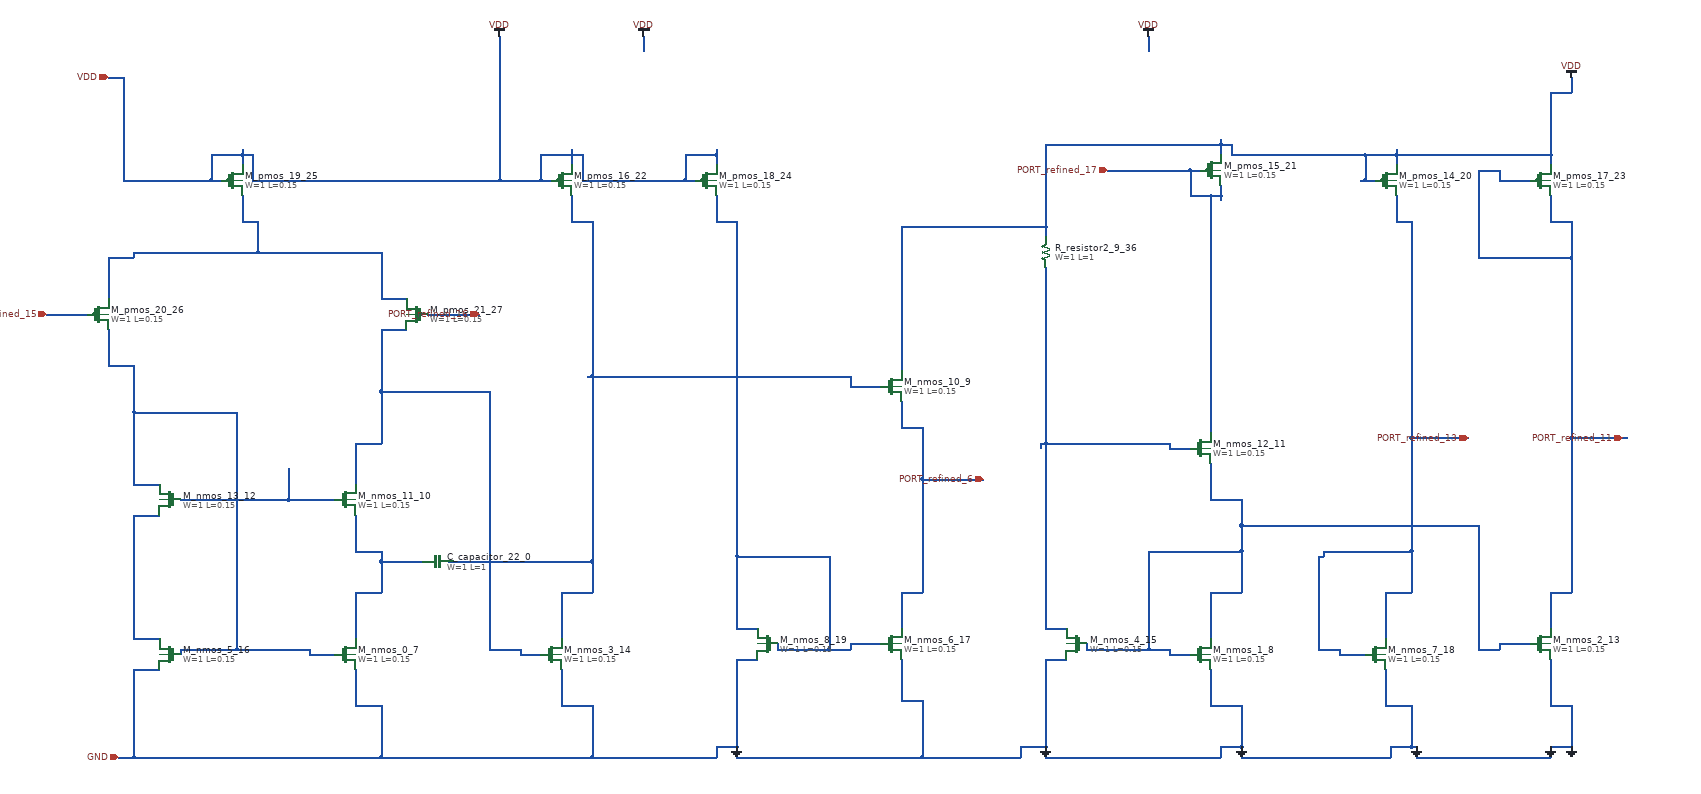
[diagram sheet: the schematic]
v {xschem version=3.4.8 file_version=1.2}
G {}
K {}
V {}
S {}
E {}
C {sky130_fd_pr/cap_mim_m3_1.sym} 920 1120 1 0 {name="C_capacitor_22_0" model=cap_mim_m3_1 W=1 L=1 MF=1 spiceprefix=X}
C {devices/gnd.sym} 3120 1480 0 0 {name="l_gnd_45_1" lab="GND"}
C {devices/gnd.sym} 1500 1480 0 0 {name="l_gnd_47_2" lab="GND"}
C {devices/gnd.sym} 2100 1480 0 0 {name="l_gnd_48_3" lab="GND"}
C {devices/gnd.sym} 3080 1480 0 0 {name="l_gnd_49_4" lab="GND"}
C {devices/gnd.sym} 2820 1480 0 0 {name="l_gnd_50_5" lab="GND"}
C {devices/gnd.sym} 2480 1480 0 0 {name="l_gnd_51_6" lab="GND"}
C {sky130_fd_pr/nfet3_01v8.sym} 740 1300 0 0 {name="M_nmos_0_7"
W=1
L=0.15
body=GND
nf=1
mult=1
ad="expr('int((@nf + 1)/2) * @W / @nf * 0.29')"
pd="expr('2*int((@nf + 1)/2) * (@W / @nf + 0.29)')"
as="expr('int((@nf + 2)/2) * @W / @nf * 0.29')"
ps="expr('2*int((@nf + 2)/2) * (@W / @nf + 0.29)')"
nrd="expr('0.29 / @W ')" nrs="expr('0.29 / @W ')"
sa=0 sb=0 sd=0
model=nfet_01v8
spiceprefix=X
}
C {sky130_fd_pr/nfet3_01v8.sym} 2400 1300 0 0 {name="M_nmos_1_8"
W=1
L=0.15
body=GND
nf=1
mult=1
ad="expr('int((@nf + 1)/2) * @W / @nf * 0.29')"
pd="expr('2*int((@nf + 1)/2) * (@W / @nf + 0.29)')"
as="expr('int((@nf + 2)/2) * @W / @nf * 0.29')"
ps="expr('2*int((@nf + 2)/2) * (@W / @nf + 0.29)')"
nrd="expr('0.29 / @W ')" nrs="expr('0.29 / @W ')"
sa=0 sb=0 sd=0
model=nfet_01v8
spiceprefix=X
}
C {sky130_fd_pr/nfet3_01v8.sym} 1800 780 0 0 {name="M_nmos_10_9"
W=1
L=0.15
body=GND
nf=1
mult=1
ad="expr('int((@nf + 1)/2) * @W / @nf * 0.29')"
pd="expr('2*int((@nf + 1)/2) * (@W / @nf + 0.29)')"
as="expr('int((@nf + 2)/2) * @W / @nf * 0.29')"
ps="expr('2*int((@nf + 2)/2) * (@W / @nf + 0.29)')"
nrd="expr('0.29 / @W ')" nrs="expr('0.29 / @W ')"
sa=0 sb=0 sd=0
model=nfet_01v8
spiceprefix=X
}
C {sky130_fd_pr/nfet3_01v8.sym} 740 1000 0 0 {name="M_nmos_11_10"
W=1
L=0.15
body=GND
nf=1
mult=1
ad="expr('int((@nf + 1)/2) * @W / @nf * 0.29')"
pd="expr('2*int((@nf + 1)/2) * (@W / @nf + 0.29)')"
as="expr('int((@nf + 2)/2) * @W / @nf * 0.29')"
ps="expr('2*int((@nf + 2)/2) * (@W / @nf + 0.29)')"
nrd="expr('0.29 / @W ')" nrs="expr('0.29 / @W ')"
sa=0 sb=0 sd=0
model=nfet_01v8
spiceprefix=X
}
C {sky130_fd_pr/nfet3_01v8.sym} 2400 900 0 0 {name="M_nmos_12_11"
W=1
L=0.15
body=GND
nf=1
mult=1
ad="expr('int((@nf + 1)/2) * @W / @nf * 0.29')"
pd="expr('2*int((@nf + 1)/2) * (@W / @nf + 0.29)')"
as="expr('int((@nf + 2)/2) * @W / @nf * 0.29')"
ps="expr('2*int((@nf + 2)/2) * (@W / @nf + 0.29)')"
nrd="expr('0.29 / @W ')" nrs="expr('0.29 / @W ')"
sa=0 sb=0 sd=0
model=nfet_01v8
spiceprefix=X
}
C {sky130_fd_pr/nfet3_01v8.sym} 400 1000 0 1 {name="M_nmos_13_12"
W=1
L=0.15
body=GND
nf=1
mult=1
ad="expr('int((@nf + 1)/2) * @W / @nf * 0.29')"
pd="expr('2*int((@nf + 1)/2) * (@W / @nf + 0.29)')"
as="expr('int((@nf + 2)/2) * @W / @nf * 0.29')"
ps="expr('2*int((@nf + 2)/2) * (@W / @nf + 0.29)')"
nrd="expr('0.29 / @W ')" nrs="expr('0.29 / @W ')"
sa=0 sb=0 sd=0
model=nfet_01v8
spiceprefix=X
}
C {sky130_fd_pr/nfet3_01v8.sym} 3060 1280 0 0 {name="M_nmos_2_13"
W=1
L=0.15
body=GND
nf=1
mult=1
ad="expr('int((@nf + 1)/2) * @W / @nf * 0.29')"
pd="expr('2*int((@nf + 1)/2) * (@W / @nf + 0.29)')"
as="expr('int((@nf + 2)/2) * @W / @nf * 0.29')"
ps="expr('2*int((@nf + 2)/2) * (@W / @nf + 0.29)')"
nrd="expr('0.29 / @W ')" nrs="expr('0.29 / @W ')"
sa=0 sb=0 sd=0
model=nfet_01v8
spiceprefix=X
}
C {sky130_fd_pr/nfet3_01v8.sym} 1140 1300 0 0 {name="M_nmos_3_14"
W=1
L=0.15
body=GND
nf=1
mult=1
ad="expr('int((@nf + 1)/2) * @W / @nf * 0.29')"
pd="expr('2*int((@nf + 1)/2) * (@W / @nf + 0.29)')"
as="expr('int((@nf + 2)/2) * @W / @nf * 0.29')"
ps="expr('2*int((@nf + 2)/2) * (@W / @nf + 0.29)')"
nrd="expr('0.29 / @W ')" nrs="expr('0.29 / @W ')"
sa=0 sb=0 sd=0
model=nfet_01v8
spiceprefix=X
}
C {sky130_fd_pr/nfet3_01v8.sym} 2160 1280 0 1 {name="M_nmos_4_15"
W=1
L=0.15
body=GND
nf=1
mult=1
ad="expr('int((@nf + 1)/2) * @W / @nf * 0.29')"
pd="expr('2*int((@nf + 1)/2) * (@W / @nf + 0.29)')"
as="expr('int((@nf + 2)/2) * @W / @nf * 0.29')"
ps="expr('2*int((@nf + 2)/2) * (@W / @nf + 0.29)')"
nrd="expr('0.29 / @W ')" nrs="expr('0.29 / @W ')"
sa=0 sb=0 sd=0
model=nfet_01v8
spiceprefix=X
}
C {sky130_fd_pr/nfet3_01v8.sym} 400 1300 0 1 {name="M_nmos_5_16"
W=1
L=0.15
body=GND
nf=1
mult=1
ad="expr('int((@nf + 1)/2) * @W / @nf * 0.29')"
pd="expr('2*int((@nf + 1)/2) * (@W / @nf + 0.29)')"
as="expr('int((@nf + 2)/2) * @W / @nf * 0.29')"
ps="expr('2*int((@nf + 2)/2) * (@W / @nf + 0.29)')"
nrd="expr('0.29 / @W ')" nrs="expr('0.29 / @W ')"
sa=0 sb=0 sd=0
model=nfet_01v8
spiceprefix=X
}
C {sky130_fd_pr/nfet3_01v8.sym} 1800 1280 0 0 {name="M_nmos_6_17"
W=1
L=0.15
body=GND
nf=1
mult=1
ad="expr('int((@nf + 1)/2) * @W / @nf * 0.29')"
pd="expr('2*int((@nf + 1)/2) * (@W / @nf + 0.29)')"
as="expr('int((@nf + 2)/2) * @W / @nf * 0.29')"
ps="expr('2*int((@nf + 2)/2) * (@W / @nf + 0.29)')"
nrd="expr('0.29 / @W ')" nrs="expr('0.29 / @W ')"
sa=0 sb=0 sd=0
model=nfet_01v8
spiceprefix=X
}
C {sky130_fd_pr/nfet3_01v8.sym} 2740 1300 0 0 {name="M_nmos_7_18"
W=1
L=0.15
body=GND
nf=1
mult=1
ad="expr('int((@nf + 1)/2) * @W / @nf * 0.29')"
pd="expr('2*int((@nf + 1)/2) * (@W / @nf + 0.29)')"
as="expr('int((@nf + 2)/2) * @W / @nf * 0.29')"
ps="expr('2*int((@nf + 2)/2) * (@W / @nf + 0.29)')"
nrd="expr('0.29 / @W ')" nrs="expr('0.29 / @W ')"
sa=0 sb=0 sd=0
model=nfet_01v8
spiceprefix=X
}
C {sky130_fd_pr/nfet3_01v8.sym} 1560 1280 0 1 {name="M_nmos_8_19"
W=1
L=0.15
body=GND
nf=1
mult=1
ad="expr('int((@nf + 1)/2) * @W / @nf * 0.29')"
pd="expr('2*int((@nf + 1)/2) * (@W / @nf + 0.29)')"
as="expr('int((@nf + 2)/2) * @W / @nf * 0.29')"
ps="expr('2*int((@nf + 2)/2) * (@W / @nf + 0.29)')"
nrd="expr('0.29 / @W ')" nrs="expr('0.29 / @W ')"
sa=0 sb=0 sd=0
model=nfet_01v8
spiceprefix=X
}
C {sky130_fd_pr/pfet3_01v8.sym} 2760 380 0 0 {name="M_pmos_14_20"
W=1
L=0.15
body=VDD
nf=1
mult=1
ad="expr('int((@nf + 1)/2) * @W / @nf * 0.29')"
pd="expr('2*int((@nf + 1)/2) * (@W / @nf + 0.29)')"
as="expr('int((@nf + 2)/2) * @W / @nf * 0.29')"
ps="expr('2*int((@nf + 2)/2) * (@W / @nf + 0.29)')"
nrd="expr('0.29 / @W ')" nrs="expr('0.29 / @W ')"
sa=0 sb=0 sd=0
model=pfet_01v8
spiceprefix=X
}
C {sky130_fd_pr/pfet3_01v8.sym} 2420 360 0 0 {name="M_pmos_15_21"
W=1
L=0.15
body=VDD
nf=1
mult=1
ad="expr('int((@nf + 1)/2) * @W / @nf * 0.29')"
pd="expr('2*int((@nf + 1)/2) * (@W / @nf + 0.29)')"
as="expr('int((@nf + 2)/2) * @W / @nf * 0.29')"
ps="expr('2*int((@nf + 2)/2) * (@W / @nf + 0.29)')"
nrd="expr('0.29 / @W ')" nrs="expr('0.29 / @W ')"
sa=0 sb=0 sd=0
model=pfet_01v8
spiceprefix=X
}
C {sky130_fd_pr/pfet3_01v8.sym} 1160 380 0 0 {name="M_pmos_16_22"
W=1
L=0.15
body=VDD
nf=1
mult=1
ad="expr('int((@nf + 1)/2) * @W / @nf * 0.29')"
pd="expr('2*int((@nf + 1)/2) * (@W / @nf + 0.29)')"
as="expr('int((@nf + 2)/2) * @W / @nf * 0.29')"
ps="expr('2*int((@nf + 2)/2) * (@W / @nf + 0.29)')"
nrd="expr('0.29 / @W ')" nrs="expr('0.29 / @W ')"
sa=0 sb=0 sd=0
model=pfet_01v8
spiceprefix=X
}
C {sky130_fd_pr/pfet3_01v8.sym} 3060 380 0 0 {name="M_pmos_17_23"
W=1
L=0.15
body=VDD
nf=1
mult=1
ad="expr('int((@nf + 1)/2) * @W / @nf * 0.29')"
pd="expr('2*int((@nf + 1)/2) * (@W / @nf + 0.29)')"
as="expr('int((@nf + 2)/2) * @W / @nf * 0.29')"
ps="expr('2*int((@nf + 2)/2) * (@W / @nf + 0.29)')"
nrd="expr('0.29 / @W ')" nrs="expr('0.29 / @W ')"
sa=0 sb=0 sd=0
model=pfet_01v8
spiceprefix=X
}
C {sky130_fd_pr/pfet3_01v8.sym} 1440 380 0 0 {name="M_pmos_18_24"
W=1
L=0.15
body=VDD
nf=1
mult=1
ad="expr('int((@nf + 1)/2) * @W / @nf * 0.29')"
pd="expr('2*int((@nf + 1)/2) * (@W / @nf + 0.29)')"
as="expr('int((@nf + 2)/2) * @W / @nf * 0.29')"
ps="expr('2*int((@nf + 2)/2) * (@W / @nf + 0.29)')"
nrd="expr('0.29 / @W ')" nrs="expr('0.29 / @W ')"
sa=0 sb=0 sd=0
model=pfet_01v8
spiceprefix=X
}
C {sky130_fd_pr/pfet3_01v8.sym} 520 380 0 0 {name="M_pmos_19_25"
W=1
L=0.15
body=VDD
nf=1
mult=1
ad="expr('int((@nf + 1)/2) * @W / @nf * 0.29')"
pd="expr('2*int((@nf + 1)/2) * (@W / @nf + 0.29)')"
as="expr('int((@nf + 2)/2) * @W / @nf * 0.29')"
ps="expr('2*int((@nf + 2)/2) * (@W / @nf + 0.29)')"
nrd="expr('0.29 / @W ')" nrs="expr('0.29 / @W ')"
sa=0 sb=0 sd=0
model=pfet_01v8
spiceprefix=X
}
C {sky130_fd_pr/pfet3_01v8.sym} 260 640 0 0 {name="M_pmos_20_26"
W=1
L=0.15
body=VDD
nf=1
mult=1
ad="expr('int((@nf + 1)/2) * @W / @nf * 0.29')"
pd="expr('2*int((@nf + 1)/2) * (@W / @nf + 0.29)')"
as="expr('int((@nf + 2)/2) * @W / @nf * 0.29')"
ps="expr('2*int((@nf + 2)/2) * (@W / @nf + 0.29)')"
nrd="expr('0.29 / @W ')" nrs="expr('0.29 / @W ')"
sa=0 sb=0 sd=0
model=pfet_01v8
spiceprefix=X
}
C {sky130_fd_pr/pfet3_01v8.sym} 880 640 0 1 {name="M_pmos_21_27"
W=1
L=0.15
body=VDD
nf=1
mult=1
ad="expr('int((@nf + 1)/2) * @W / @nf * 0.29')"
pd="expr('2*int((@nf + 1)/2) * (@W / @nf + 0.29)')"
as="expr('int((@nf + 2)/2) * @W / @nf * 0.29')"
ps="expr('2*int((@nf + 2)/2) * (@W / @nf + 0.29)')"
nrd="expr('0.29 / @W ')" nrs="expr('0.29 / @W ')"
sa=0 sb=0 sd=0
model=pfet_01v8
spiceprefix=X
}
C {devices/ipin.sym} 1980 960 0 0 {name="p_port_23_28" lab="PORT_refined_6"}
C {devices/ipin.sym} 2920 880 0 0 {name="p_port_24_29" lab="PORT_refined_13"}
C {devices/ipin.sym} 3220 880 0 0 {name="p_port_25_30" lab="PORT_refined_11"}
C {devices/ipin.sym} 1000 640 0 0 {name="p_port_26_31" lab="PORT_refined_16"}
C {devices/ipin.sym} 160 640 0 0 {name="p_port_27_32" lab="PORT_refined_15"}
C {devices/ipin.sym} 2220 360 0 0 {name="p_port_28_33" lab="PORT_refined_17"}
C {devices/ipin.sym} 300 1500 0 0 {name="p_port_29_34" lab="GND"}
C {devices/ipin.sym} 280 180 0 0 {name="p_port_30_35" lab="VDD"}
C {sky130_fd_pr/res_generic_po.sym} 2100 520 2 0 {name="R_resistor2_9_36"
W=1
L=1
model=res_generic_po
spiceprefix=X
mult=1}
C {devices/vdd.sym} 3120 180 0 0 {name="l_vdd_35_37" lab="VDD"}
C {devices/vdd.sym} 1320 100 0 0 {name="l_vdd_41_38" lab="VDD"}
C {devices/vdd.sym} 2300 100 0 0 {name="l_vdd_44_39" lab="VDD"}
C {devices/vdd.sym} 1040 100 0 0 {name="l_vdd_46_40" lab="VDD"}
N 760 1180 810 1180 {}
N 810 1120 890 1120 {}
N 760 1100 810 1100 {}
N 760 1270 760 1180 {}
N 760 1100 760 1030 {}
N 810 1180 810 1120 {}
N 810 1120 810 1100 {}
N 1160 1180 1220 1180 {}
N 940 1120 950 1120 {}
N 950 1120 1220 1120 {}
N 1720 780 1780 780 {}
N 1210 760 1220 760 {}
N 1220 760 1720 760 {}
N 1180 460 1220 460 {}
N 1160 1270 1160 1180 {}
N 1180 460 1180 410 {}
N 1220 1180 1220 1120 {}
N 1220 1120 1220 760 {}
N 1220 760 1220 460 {}
N 1720 780 1720 760 {}
N 330 1270 380 1270 {}
N 330 1030 380 1030 {}
N 330 1270 330 1030 {}
N 3080 1180 3120 1180 {}
N 3120 880 3220 880 {}
N 3220 880 3230 880 {}
N 2940 530 3120 530 {}
N 3080 460 3120 460 {}
N 2980 380 3040 380 {}
N 2940 360 2980 360 {}
N 2940 530 2940 360 {}
N 2980 380 2980 360 {}
N 3080 1250 3080 1180 {}
N 3080 460 3080 410 {}
N 3120 1180 3120 880 {}
N 3120 880 3120 530 {}
N 3120 530 3120 460 {}
N 1580 1290 1680 1290 {}
N 1680 1290 1720 1290 {}
N 1720 1280 1780 1280 {}
N 1500 1250 1540 1250 {}
N 1500 1110 1680 1110 {}
N 1460 460 1500 460 {}
N 1460 460 1460 410 {}
N 1500 1250 1500 1110 {}
N 1500 1110 1500 460 {}
N 1580 1290 1580 1280 {}
N 1680 1290 1680 1110 {}
N 1720 1290 1720 1280 {}
N 2670 1300 2720 1300 {}
N 2630 1290 2670 1290 {}
N 2760 1180 2810 1180 {}
N 2630 1110 2640 1110 {}
N 2640 1100 2810 1100 {}
N 2810 880 2920 880 {}
N 2780 460 2810 460 {}
N 2630 1290 2630 1110 {}
N 2640 1110 2640 1100 {}
N 2670 1300 2670 1290 {}
N 2760 1270 2760 1180 {}
N 2780 460 2780 410 {}
N 2810 1180 2810 1100 {}
N 2810 1100 2810 880 {}
N 2810 880 2810 460 {}
N 810 610 860 610 {}
N 280 530 330 530 {}
N 330 520 570 520 {}
N 570 520 810 520 {}
N 540 460 570 460 {}
N 280 610 280 530 {}
N 330 530 330 520 {}
N 540 460 540 410 {}
N 570 520 570 460 {}
N 810 610 810 520 {}
N 160 640 240 640 {}
N 900 640 1000 640 {}
N 2380 410 2420 410 {}
N 2420 410 2440 410 {}
N 2220 360 2380 360 {}
N 2380 360 2400 360 {}
N 2380 410 2380 360 {}
N 2420 870 2420 410 {}
N 2440 420 2440 410 {}
N 2440 410 2440 390 {}
N 670 1300 720 1300 {}
N 420 1290 530 1290 {}
N 530 1290 670 1290 {}
N 330 970 380 970 {}
N 330 830 530 830 {}
N 280 740 330 740 {}
N 280 740 280 670 {}
N 330 970 330 830 {}
N 330 830 330 740 {}
N 420 1300 420 1290 {}
N 530 1290 530 830 {}
N 670 1300 670 1290 {}
N 2340 1300 2380 1300 {}
N 2180 1290 2300 1290 {}
N 2300 1290 2340 1290 {}
N 2940 1290 2980 1290 {}
N 2980 1280 3040 1280 {}
N 2420 1180 2480 1180 {}
N 2300 1100 2480 1100 {}
N 2480 1050 2940 1050 {}
N 2420 1000 2480 1000 {}
N 2180 1290 2180 1280 {}
N 2300 1290 2300 1100 {}
N 2340 1300 2340 1290 {}
N 2420 1270 2420 1180 {}
N 2420 1000 2420 930 {}
N 2480 1180 2480 1100 {}
N 2480 1100 2480 1050 {}
N 2480 1050 2480 1000 {}
N 2940 1290 2940 1050 {}
N 2980 1290 2980 1280 {}
N 300 1500 330 1500 {}
N 330 1500 810 1500 {}
N 810 1500 1220 1500 {}
N 1220 1500 1460 1500 {}
N 1500 1500 1860 1500 {}
N 1860 1500 2050 1500 {}
N 2100 1500 2440 1500 {}
N 2480 1500 2770 1500 {}
N 2820 1500 3080 1500 {}
N 1460 1480 1500 1480 {}
N 2050 1480 2100 1480 {}
N 2440 1480 2480 1480 {}
N 2770 1480 2810 1480 {}
N 2810 1480 2820 1480 {}
N 3080 1480 3120 1480 {}
N 760 1400 810 1400 {}
N 1160 1400 1220 1400 {}
N 2420 1400 2480 1400 {}
N 2760 1400 2810 1400 {}
N 3080 1400 3120 1400 {}
N 1820 1390 1860 1390 {}
N 330 1330 380 1330 {}
N 1500 1310 1540 1310 {}
N 2100 1310 2140 1310 {}
N 330 1500 330 1330 {}
N 760 1400 760 1330 {}
N 810 1500 810 1400 {}
N 1160 1400 1160 1330 {}
N 1220 1500 1220 1400 {}
N 1460 1500 1460 1480 {}
N 1500 1500 1500 1480 {}
N 1500 1480 1500 1310 {}
N 1820 1390 1820 1310 {}
N 1860 1500 1860 1390 {}
N 2050 1500 2050 1480 {}
N 2100 1500 2100 1480 {}
N 2100 1480 2100 1310 {}
N 2420 1400 2420 1330 {}
N 2440 1500 2440 1480 {}
N 2480 1500 2480 1480 {}
N 2480 1480 2480 1400 {}
N 2760 1400 2760 1330 {}
N 2770 1500 2770 1480 {}
N 2810 1480 2810 1400 {}
N 2820 1500 2820 1480 {}
N 3080 1500 3080 1480 {}
N 3080 1400 3080 1310 {}
N 3120 1480 3120 1400 {}
N 1820 470 2100 470 {}
N 310 380 480 380 {}
N 480 380 500 380 {}
N 560 380 1040 380 {}
N 1040 380 1120 380 {}
N 1120 380 1140 380 {}
N 1200 380 1400 380 {}
N 1400 380 1420 380 {}
N 2710 380 2720 380 {}
N 2720 380 2740 380 {}
N 480 330 540 330 {}
N 540 330 560 330 {}
N 1120 330 1180 330 {}
N 1180 330 1200 330 {}
N 1400 330 1460 330 {}
N 2460 330 2720 330 {}
N 2720 330 2780 330 {}
N 2780 330 3080 330 {}
N 2100 310 2440 310 {}
N 2440 310 2460 310 {}
N 3080 210 3120 210 {}
N 280 180 310 180 {}
N 310 380 310 180 {}
N 480 380 480 330 {}
N 540 350 540 330 {}
N 540 330 540 320 {}
N 560 380 560 330 {}
N 1040 380 1040 100 {}
N 1120 380 1120 330 {}
N 1180 350 1180 330 {}
N 1180 330 1180 320 {}
N 1200 380 1200 330 {}
N 1320 130 1320 100 {}
N 1400 380 1400 330 {}
N 1460 350 1460 330 {}
N 1460 330 1460 320 {}
N 1820 750 1820 470 {}
N 2100 490 2100 470 {}
N 2100 470 2100 310 {}
N 2300 130 2300 100 {}
N 2440 330 2440 310 {}
N 2440 310 2440 300 {}
N 2460 330 2460 310 {}
N 2720 380 2720 330 {}
N 2780 350 2780 330 {}
N 2780 330 2780 320 {}
N 3080 350 3080 330 {}
N 3080 330 3080 210 {}
N 3120 210 3120 180 {}
N 1820 1180 1860 1180 {}
N 1860 960 1980 960 {}
N 1820 860 1860 860 {}
N 1820 1250 1820 1180 {}
N 1820 860 1820 810 {}
N 1860 1180 1860 960 {}
N 1860 960 1860 860 {}
N 1080 1300 1120 1300 {}
N 1020 1290 1080 1290 {}
N 760 890 810 890 {}
N 810 790 1020 790 {}
N 810 670 860 670 {}
N 760 970 760 890 {}
N 810 890 810 790 {}
N 810 790 810 670 {}
N 1020 1290 1020 790 {}
N 1080 1300 1080 1290 {}
N 420 1000 630 1000 {}
N 630 1000 720 1000 {}
N 630 1000 630 940 {}
N 2100 1250 2140 1250 {}
N 2340 900 2380 900 {}
N 2090 890 2100 890 {}
N 2100 890 2340 890 {}
N 2090 900 2090 890 {}
N 2100 1250 2100 890 {}
N 2100 890 2100 550 {}
N 2340 900 2340 890 {}
